! (c) 2009  Infineon Technologies AG, Munich
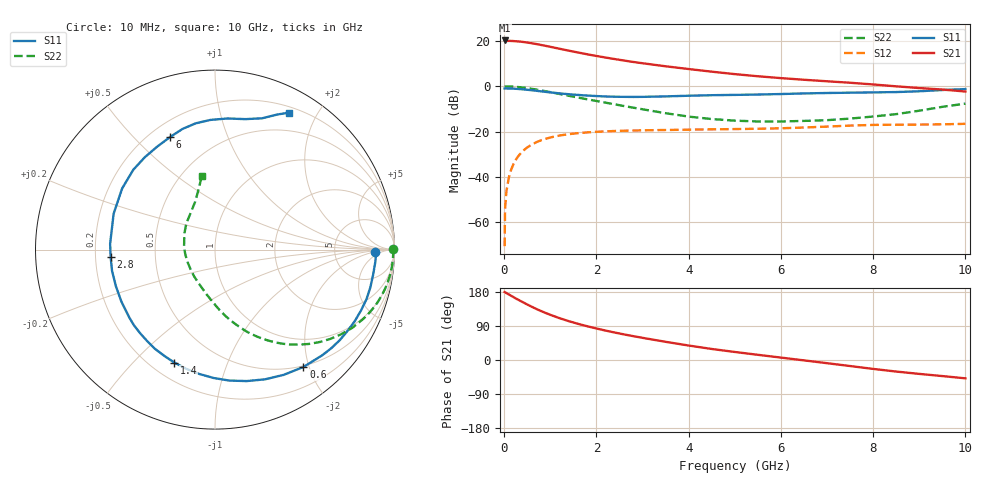
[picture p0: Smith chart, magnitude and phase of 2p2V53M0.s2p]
! Infineon Technologies  Discrete & RF Semiconductors
! BFP420
! VCE =  2.5 V,  IC =  3.0 mA
! Common Emitter S-Parameters:  Nov 2009
# GHz  S  MA  R  50
!  f  S11  S21  S12  S22
! GHz  MAG  ANG  MAG  ANG  MAG  ANG  MAG  ANG
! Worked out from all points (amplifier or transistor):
!   46 points, 10 MHz to 10 GHz, reference 50 ohm
!   highest |S21| = 20.2 dB at 10 MHz (marker M1)
!   |S21| within 3 dB of that: start of sweep to 1.047 GHz
!   unconditionally stable (mu >= 1): start of sweep to 10.4 MHz; 3.525 GHz to end of sweep
!   at 300 MHz: K = 0.06, MSG = 25.4 dB, |S12| = -31.0 dB
!   at 1.7 GHz: K = 0.44, MSG = 17.5 dB, |S12| = -20.5 dB
!   at 10 GHz: K = 1.17, MAG = 4.6 dB, |S12| = -16.5 dB
!   lowest NFmin = 0.57 dB at 900 MHz
!   S11 on the Smith chart (normalised r, x): 10 MHz: 17, -3; 600 MHz: 0.48, -1.91; 1.4 GHz: 0.29, -0.66; 2.8 GHz: 0.26, -0.03; 6 GHz: 0.28, +0.64; 10 GHz: 0.27, +1.65
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0.01  0.8933 -1.0  10.23 179.3  0.0003 36.9  0.9922 0.1
0.02  0.8974 -2.0  9.951 178.8  0.002 81.6  0.9932 -1.0
0.05  0.8958 -4.4  9.985 176.5  0.0049 86.2  0.9928 -2.6
0.1  0.892 -9.2  10.02 173.1  0.0096 84.8  0.9907 -5.2
0.2  0.8881 -18.1  9.931 166.2  0.0191 79.8  0.9799 -10.5
0.35  0.8662 -31.6  9.639 156.1  0.0326 72.7  0.9517 -18.1
0.5  0.8388 -44.6  9.209 146.5  0.0449 65.8  0.9109 -25.2
0.6  0.8187 -53.0  8.882 140.4  0.0521 61.5  0.8801 -29.7
0.7  0.7961 -61.2  8.527 134.6  0.0587 57.4  0.8463 -33.9
0.9  0.7536 -76.4  7.777 124.1  0.0697 50.1  0.7776 -41.5
1.2  0.6983 -97.3  6.723 110.4  0.0821 41.1  0.678 -51.3
1.4  0.6688 -109.8  6.101 102.5  0.088 36.1  0.6187 -56.8
1.7  0.6341 -126.7  5.32 92.2  0.0947 30.0  0.5406 -64.0
2.2  0.5966 -151.0  4.3 77.6  0.1017 22.1  0.4357 -74.1
2.8  0.5829 -176.1  3.44 62.9  0.1061 15.0  0.338 -85.6
3.5  0.5991 160.5  2.761 48.0  0.1089 9.2  0.2554 -100.3
4.5  0.6365 135.7  2.101 29.1  0.1125 3.5  0.1899 -127.4
5.5  0.658 119.2  1.664 13.7  0.116 -0.2  0.1679 -155.5
6  0.6755 111.7  1.515 6.4  0.1188 -1.5  0.1676 -170.5
7  0.7117 98.7  1.29 -8.4  0.1295 -5.1  0.1793 163.2
8.5  0.7463 76.9  0.998 -30.5  0.1423 -15.8  0.2435 124.2
10  0.8679 61.6  0.767 -48.4  0.1489 -22.6  0.4153 100.3
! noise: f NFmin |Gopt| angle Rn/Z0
0.9  0.57  0.35  33  0.18
1.8  1.02  0.2  79  0.14
2.4  1.1  0.23  104  0.14
3  1.25  0.24  144  0.11
4  1.46  0.33  -159  0.1
5  1.9  0.39  -128  0.22
6  2.46  0.48  -107  0.35
